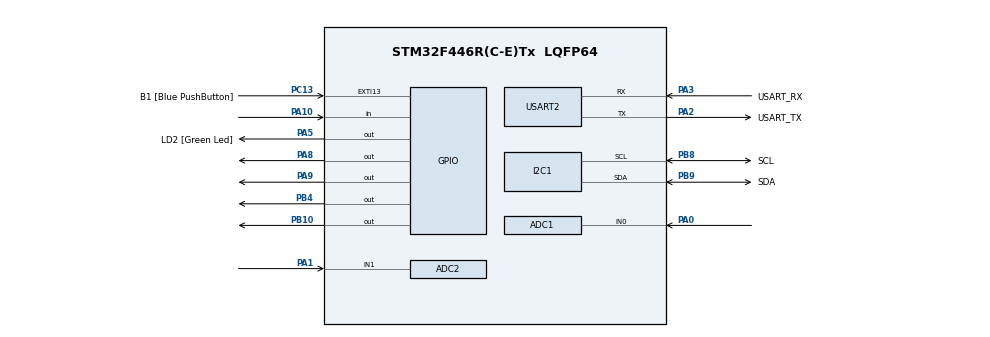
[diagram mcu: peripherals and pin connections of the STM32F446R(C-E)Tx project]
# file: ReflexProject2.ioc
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ADC1.Channel-4\#ChannelRegularConversion=ADC_CHANNEL_0
ADC1.ClockPrescaler=ADC_CLOCK_SYNC_PCLK_DIV4
ADC1.ContinuousConvMode=ENABLE
ADC1.DMAContinuousRequestsForConfigFile-ADC_Settings=LIMITED
ADC1.DataAlign=ADC_DATAALIGN_RIGHT
ADC1.InjNumberOfConversion=0
ADC1.Mode=__NULL
ADC1.NbrOfConversionFlag=1
ADC1.Rank-4\#ChannelRegularConversion=1
ADC1.Resolution=ADC_RESOLUTION_12B
ADC1.SamplingTime-4\#ChannelRegularConversion=ADC_SAMPLETIME_3CYCLES
ADC1.master=1
ADC2.Channel-2\#ChannelRegularConversion=ADC_CHANNEL_1
ADC2.ClockPrescaler=ADC_CLOCK_SYNC_PCLK_DIV4
ADC2.ContinuousConvMode=ENABLE
ADC2.DMAContinuousRequestsForConfigFile-ADC_Settings=LIMITED
ADC2.NbrOfConversionFlag=1
ADC2.Rank-2\#ChannelRegularConversion=1
ADC2.SamplingTime-2\#ChannelRegularConversion=ADC_SAMPLETIME_3CYCLES
Dma.I2C1_RX.1.Direction=DMA_PERIPH_TO_MEMORY
Dma.I2C1_RX.1.FIFOMode=DMA_FIFOMODE_DISABLE
Dma.I2C1_RX.1.Instance=DMA1_Stream0
Dma.I2C1_RX.1.MemDataAlignment=DMA_MDATAALIGN_BYTE
Dma.I2C1_RX.1.MemInc=DMA_MINC_ENABLE
Dma.I2C1_RX.1.Mode=DMA_NORMAL
Dma.I2C1_RX.1.PeriphDataAlignment=DMA_PDATAALIGN_BYTE
Dma.I2C1_RX.1.PeriphInc=DMA_PINC_DISABLE
Dma.I2C1_RX.1.Priority=DMA_PRIORITY_LOW
Dma.I2C1_TX.0.Direction=DMA_MEMORY_TO_PERIPH
Dma.I2C1_TX.0.FIFOMode=DMA_FIFOMODE_DISABLE
Dma.I2C1_TX.0.Instance=DMA1_Stream6
Dma.I2C1_TX.0.MemDataAlignment=DMA_MDATAALIGN_BYTE
Dma.I2C1_TX.0.MemInc=DMA_MINC_ENABLE
Dma.I2C1_TX.0.Mode=DMA_NORMAL
Dma.I2C1_TX.0.PeriphDataAlignment=DMA_PDATAALIGN_BYTE
Dma.I2C1_TX.0.PeriphInc=DMA_PINC_DISABLE
Dma.I2C1_TX.0.Priority=DMA_PRIORITY_LOW
Dma.Request0=I2C1_TX
Dma.Request1=I2C1_RX
FREERTOS.BinarySemaphores01=semaphoreTest,Dynamic,NULL;semaphoreMenuTimerTemp,Dynamic,NULL
FREERTOS.Queues01=potenValue,16,uint16_t,0,Dynamic,NULL,NULL
FREERTOS.Tasks01=defaultTask,24,128,StartDefaultTask,Default,NULL,Dynamic,NULL,NULL;GereLeds,24,128,GereLeds_1,Default,NULL,Dynamic,NULL,NULL;GereLcdScreen,8,128,GereLcdScreen_1,Default,NULL,Dynamic,NULL,NULL;gereRGB_LCD,8,128,changeRGBs,Default,NULL,Dynamic,NULL,NULL;gerePoten_AD0,10,128,getValueAdc,Default,NULL,Dynamic,NULL,NULL;personnalDelays,8,128,gereDelays,Default,NULL,Dynamic,NULL,NULL;stateDiagram,25,128,gereStateDiagram,Default,NULL,Dynamic,NULL,NULL
FREERTOS.configUSE_NEWLIB_REENTRANT=1
Mcu.Family=STM32F4
Mcu.Name=STM32F446R(C-E)Tx
Mcu.Package=LQFP64
NVIC.DMA1_Stream0_IRQn=true\:5\:0\:false\:false\:true\:true\:false\:true\:true
NVIC.DMA1_Stream6_IRQn=true\:5\:0\:false\:false\:true\:true\:false\:true\:true
NVIC.I2C1_ER_IRQn=true\:5\:0\:false\:false\:true\:true\:true\:true\:true
NVIC.I2C1_EV_IRQn=true\:5\:0\:false\:false\:true\:true\:true\:true\:true
NVIC.PriorityGroup=NVIC_PRIORITYGROUP_4
NVIC.TIM2_IRQn=true\:5\:0\:false\:false\:true\:true\:true\:true\:true
NVIC.TIM6_DAC_IRQn=true\:15\:0\:false\:false\:true\:false\:false\:true\:true
NVIC.TimeBase=TIM6_DAC_IRQn
NVIC.TimeBaseIP=TIM6
PA0-WKUP.Signal=ADCx_IN0
PA1.Signal=ADCx_IN1
PA10.Signal=GPIO_Input
PA13.GPIO_Label=TMS
PA13.Mode=Trace_Asynchronous_SW
PA13.Signal=SYS_JTMS-SWDIO
PA14.GPIO_Label=TCK
PA14.Mode=Trace_Asynchronous_SW
PA14.Signal=SYS_JTCK-SWCLK
PA2.GPIO_Label=USART_TX
PA2.Mode=Asynchronous
PA2.Signal=USART2_TX
PA3.GPIO_Label=USART_RX
PA3.Mode=Asynchronous
PA3.Signal=USART2_RX
PA5.GPIO_Label=LD2 [Green Led]
PA5.Signal=GPIO_Output
PA8.Signal=GPIO_Output
PA9.Signal=GPIO_Output
PB10.Signal=GPIO_Output
PB3.GPIO_Label=SWO
PB3.Mode=Trace_Asynchronous_SW
PB3.Signal=SYS_JTDO-SWO
PB4.Signal=GPIO_Output
PB8.GPIO_Label=SCL
PB8.GPIO_Pu=GPIO_PULLUP
PB8.Mode=I2C
PB8.Signal=I2C1_SCL
PB9.GPIO_Label=SDA
PB9.GPIO_Pu=GPIO_PULLUP
PB9.Mode=I2C
PB9.Signal=I2C1_SDA
PC13.GPIO_Label=B1 [Blue PushButton]
PC13.GPIO_ModeDefaultEXTI=GPIO_MODE_IT_FALLING
PC13.Signal=GPXTI13
PC14-OSC32_IN.Signal=RCC_OSC32_IN
PC15-OSC32_OUT.Signal=RCC_OSC32_OUT
PH0-OSC_IN.Mode=HSE-External-Oscillator
PH0-OSC_IN.Signal=RCC_OSC_IN
PH1-OSC_OUT.Mode=HSE-External-Oscillator
PH1-OSC_OUT.Signal=RCC_OSC_OUT
ProjectManager.HeapSize=0x200
ProjectManager.StackSize=0x400
ProjectManager.TargetToolchain=STM32CubeIDE
RCC.48MHZClocksFreq_Value=84000000
RCC.AHBCLKDivider=RCC_SYSCLK_DIV2
RCC.AHBFreq_Value=4000000
RCC.APB1CLKDivider=RCC_HCLK_DIV2
RCC.APB1Freq_Value=2000000
RCC.APB1TimFreq_Value=4000000
RCC.APB2Freq_Value=4000000
RCC.APB2TimFreq_Value=4000000
RCC.CortexFreq_Value=4000000
RCC.FLatency-AdvancedSettings=FLASH_LATENCY_0
RCC.HCLKFreq_Value=4000000
RCC.HSE_VALUE=8000000
RCC.HSI_VALUE=16000000
RCC.PLLN=336
RCC.PLLP=RCC_PLLP_DIV4
RCC.SYSCLKFreq_VALUE=8000000
RCC.SYSCLKSource=RCC_SYSCLKSOURCE_HSE
RCC.USBFreq_Value=168000000
RCC.VCOOutputFreq_Value=336000000
SH.ADCx_IN0.0=ADC1_IN0,IN0
SH.ADCx_IN1.0=ADC2_IN1,IN1
TIM2.Period=4000
TIM2.Prescaler=100
USART2.VirtualMode=VM_ASYNC
VP_FREERTOS_VS_CMSIS_V2.Mode=CMSIS_V2
VP_SYS_VS_tim6.Mode=TIM6
VP_TIM2_VS_ClockSourceINT.Mode=Internal
board=NUCLEO-F446RE

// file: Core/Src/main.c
/* USER CODE BEGIN Header */
/**
 ******************************************************************************
 * @file           : main.c
 * @brief          : Main program body
 ******************************************************************************
 * @attention
 *
 * Copyright (c) 2023 STMicroelectronics.
 * All rights reserved.
 *
 * This software is licensed under terms that can be found in the LICENSE file
 * in the root directory of this software component.
 * If no LICENSE file comes with this software, it is provided AS-IS.
 *
 ******************************************************************************
 */
/* USER CODE END Header */
#include "main.h"

#include "cmsis_os.h"

/* USER CODE BEGIN Includes */

#include "rgb_lcd.h"

#include "stdio.h"

#include "string.h"

#include "stdlib.h"

#include <time.h>
 //#include "cmsis_os2.h"

/* USER CODE END Includes */

/* USER CODE BEGIN PD */

#define NBR_COL 18

/* USER CODE END PD */

ADC_HandleTypeDef hadc1;
ADC_HandleTypeDef hadc2;

I2C_HandleTypeDef hi2c1;
DMA_HandleTypeDef hdma_i2c1_tx;
DMA_HandleTypeDef hdma_i2c1_rx;

TIM_HandleTypeDef htim2;

UART_HandleTypeDef huart2;

/* Definitions for defaultTask */
osThreadId_t defaultTaskHandle;
const osThreadAttr_t defaultTask_attributes = {
    .name = "defaultTask",
    .stack_size = 128 * 4,
    .priority = (osPriority_t) osPriorityNormal,
};
/* Definitions for GereLeds */
osThreadId_t GereLedsHandle;
const osThreadAttr_t GereLeds_attributes = {
    .name = "GereLeds",
    .stack_size = 128 * 4,
    .priority = (osPriority_t) osPriorityNormal,
};
/* Definitions for GereLcdScreen */
osThreadId_t LedsControlHandle;
const osThreadAttr_t LedsControl_attributes = {
    .name = "LedsControl",
    .stack_size = 128 * 4,
    .priority = (osPriority_t) osPriorityNormal,
};
/* Definitions for gereRGB_LCD */
osThreadId_t gereRGB_LCDHandle;
const osThreadAttr_t gereRGB_LCD_attributes = {
    .name = "gereRGB_LCD",
    .stack_size = 128 * 4,
    .priority = (osPriority_t) osPriorityNormal,
};
/* Definitions for gerePoten_AD0 */
osThreadId_t gerePoten_AD0Handle;
const osThreadAttr_t gerePoten_AD0_attributes = {
    .name = "gerePoten_AD0",
    .stack_size = 128 * 4,
    .priority = (osPriority_t) osPriorityNormal,
};
/* Definitions for personnalDelays */
osThreadId_t personnalDelaysHandle;
const osThreadAttr_t personnalDelays_attributes = {
    .name = "personnalDelays",
    .stack_size = 128 * 4,
    .priority = (osPriority_t) osPriorityNormal,
};
/* Definitions for stateDiagram */
osThreadId_t stateDiagramHandle;
const osThreadAttr_t stateDiagram_attributes = {
    .name = "stateDiagram",
    .stack_size = 128 * 4,
    .priority = (osPriority_t) osPriorityNormal,
};
/* Definitions for potenValue */
osMessageQueueId_t potenValueHandle;
const osMessageQueueAttr_t potenValue_attributes = {
    .name = "potenValue"
};
/* Definitions for semaphoreTest */
osSemaphoreId_t semaphoreTestHandle;
const osSemaphoreAttr_t semaphoreTest_attributes = {
    .name = "semaphoreTest"
};
/* Definitions for semaphoreMenuTimerTemp */
osSemaphoreId_t semaphoreMenuTimerTempHandle;
const osSemaphoreAttr_t semaphoreMenuTimerTemp_attributes = {
    .name = "semaphoreMenuTimerTemp"
};

/* USER CODE BEGIN PV */

/* Definitions for personnalDelays */
osThreadId_t gereMicHandle;
const osThreadAttr_t gereMic_attributes = {
    .name = "gereMic",
    .stack_size = 128 * 4,
    .priority = (osPriority_t) osPriorityNormal,
};

/* Definitions for potenValue */
osMessageQueueId_t micValueHandle;
const osMessageQueueAttr_t micValue_attributes = {
    .name = "micValue"
};

/* Definitions for semaphoreTest */
osSemaphoreId_t semaphoreValidMicroHandle;
const osSemaphoreAttr_t semaphoreValidMicro_attributes = {
    .name = "semaphoreValidMicro"
};

/* Definitions for stateDiagram */
osThreadId_t gereScoresHandle;
const osThreadAttr_t gereScores_attributes = {
    .name = "gereScores",
    .stack_size = 128 * 4,
    .priority = (osPriority_t) osPriorityNormal,
};

/* Definitions for semaphoreTest */
osSemaphoreId_t semaphoreDisplayScoresHandle;
const osSemaphoreAttr_t semaphoreDisplayScores_attributes = {
    .name = "semaphoreDisplayScores"
};

/* Definitions for semaphoreTest */
osSemaphoreId_t semaphoreEtatHautHandle;
const osSemaphoreAttr_t semaphoreEtatHaut_attributes = {
    .name = "semaphoreEtatHaut"
};

enum Etats {
    STARTING,
    MENU,
    TEST_1,
    TEST_2,
    TEST_3,
    SCORES
};

enum Etats etatCourant = STARTING;

int ignoreSemaphore = 0b11;
uint16_t potenValue = 0;
uint16_t micValue = 0;
char potenValue_string[20];
char micValue_string[20];

uint16_t soundSensorValue = 0;
char soundSensorValue_string[20];

int potenValueTemp = 0;

int idGame = 0;

uint8_t fullcharacter[] = {
    0b11111,
    0b11111,
    0b11111,
    0b11111,
    0b11111,
    0b11111,
    0b11111,
    0b11111
};

uint8_t emptycharacter[] = {
    0b00000,
    0b00000,
    0b00000,
    0b00000,
    0b00000,
    0b00000,
    0b00000,
    0b00000
};

// var for the firsts passages
int tempFirst = 0;

int bestRecord = 0;
char bestRecord_string[20];

int validMic = 0;
int bestRecord_temp = 0;
int timer_temp = 0;
int cpt_valMax = 0;
int oldValueMic = 0;

int bestRecordJeu1 = 0;
int bestRecordJeu2 = 0;
char bestRecordJeu1_string[20];
char bestRecordJeu2_string[20];

int etatLeds = 0;

size_t screenSize = sizeof("HUMAN SPEED TEST") - 1;

/* USER CODE END PV */

void SystemClock_Config(void);
static void MX_GPIO_Init(void);
static void MX_DMA_Init(void);
static void MX_USART2_UART_Init(void);
static void MX_ADC1_Init(void);
static void MX_ADC2_Init(void);
static void MX_I2C1_Init(void);
static void MX_TIM2_Init(void);
void StartDefaultTask(void * argument);
void GereLeds_1(void * argument);
void LedsControl(void * argument);
void changeRGBs(void * argument);
void getValueAdc(void * argument);
void gereDelays(void * argument);
void gereStateDiagram(void * argument);

/* USER CODE BEGIN PFP */

void startingLCD(void);
void menuLCD(void);
void getValueMic(void * argument);
void gereScores(void * argument);
void displayScores(void);

/* USER CODE END PFP */

/* USER CODE BEGIN 0 */

void displayTest1(void) {
    ignoreSemaphore = 0b11;
    LCD_clear();

    LCD_home();
    LCD_setCursor(0, 0);
    LCD_print("      JEU 1     ", screenSize);
    HAL_GPIO_WritePin(GPIOB, GPIO_PIN_10, 1);
    HAL_GPIO_WritePin(GPIOA, GPIO_PIN_8, 1);
    HAL_GPIO_WritePin(GPIOA, GPIO_PIN_9, 1);
    LCD_setCursor(0, 1);
    LCD_print("                ", screenSize);
    osDelay(1000);
    HAL_GPIO_WritePin(GPIOA, GPIO_PIN_8, 0);
    HAL_GPIO_WritePin(GPIOA, GPIO_PIN_9, 0);
    LCD_setCursor(0, 0);
    LCD_print("        3       ", screenSize);
    osDelay(1000);
    LCD_setCursor(0, 0);
    LCD_print("        2       ", screenSize);
    HAL_GPIO_WritePin(GPIOA, GPIO_PIN_9, 1);
    osDelay(1000);
    LCD_setCursor(0, 0);
    LCD_print("        1       ", screenSize);
    HAL_GPIO_WritePin(GPIOA, GPIO_PIN_8, 1);
    osDelay(1000);
    HAL_GPIO_WritePin(GPIOB, GPIO_PIN_10, 0);
    HAL_GPIO_WritePin(GPIOA, GPIO_PIN_8, 0);
    HAL_GPIO_WritePin(GPIOA, GPIO_PIN_9, 0);
    etatLeds = 1;
    LCD_setCursor(0, 0);
    LCD_print("      WAIT      ", screenSize);
    osDelay(1000);

    int cpt;
    int r = rand(); // Returns a pseudo-random integer between 0 and RAND_MAX.
    r = r % 5000000;

    char aye_string[16];
    int aye_res;
    bestRecord = 0;
    TIM2 -> CNT = 0;
    while (r >= cpt) {
        cpt = (bestRecord * 1000000) + ((TIM2 -> CNT) / 4);
    }
    etatLeds = 0;
    HAL_GPIO_WritePin(GPIOA, GPIO_PIN_8, 1);
    LCD_setCursor(0, 0);
    LCD_print("     PUSH       ", screenSize);
    bestRecord = 0;
    TIM2 -> CNT = 0;
    cpt = 0;
    ignoreSemaphore = 0b01;
    int iVerif = osSemaphoreAcquire(semaphoreEtatHautHandle, 5000);
    ignoreSemaphore = 0b11;
    if (iVerif == osOK) {

        cpt = (bestRecord * 1000000) + ((TIM2 -> CNT) / 4);
        aye_res = cpt;
        HAL_GPIO_WritePin(GPIOA, GPIO_PIN_8, 0);

        sprintf(aye_string, "%d", aye_res);
        LCD_setCursor(0, 1);
        LCD_print(aye_string, screenSize);
        osDelay(5000);
        if (cpt < bestRecordJeu1) {
            bestRecordJeu1 = cpt;
            strcpy(bestRecordJeu1_string, aye_string);
        }

    } else if (iVerif == osErrorTimeout) {
        LCD_setCursor(0, 1);
        LCD_print("   TROP LENT   ", screenSize);
        osDelay(5000);
    }
    LCD_setCursor(0, 0);
    LCD_print("  PRESS - PLAY  ", screenSize);
    LCD_setCursor(0, 1);
    LCD_print("   WAIT - MENU  ", screenSize);
    ignoreSemaphore = 0b10;
    iVerif = osSemaphoreAcquire(semaphoreTestHandle, 5000);
    ignoreSemaphore = 0b11;
    if (iVerif == osErrorTimeout) {
        etatCourant = MENU;
    }
}

void displayTest2(void) {
    ignoreSemaphore = 0b11;
    LCD_clear();

    LCD_home();
    LCD_setCursor(0, 0);
    LCD_print("      JEU 2     ", screenSize);
    LCD_setCursor(0, 1);
    LCD_print("                ", screenSize);
    osDelay(1000);
    LCD_setCursor(0, 0);
    LCD_print("        3       ", screenSize);
    osDelay(1000);
    LCD_setCursor(0, 0);
    LCD_print("        2       ", screenSize);
    osDelay(1000);
    LCD_setCursor(0, 0);
    LCD_print("        1       ", screenSize);
    osDelay(1000);
    LCD_setCursor(0, 0);
    LCD_print("      WAIT      ", screenSize);
    osDelay(1000);

    int cpt;
    int r = rand(); // Returns a pseudo-random integer between 0 and RAND_MAX.
    r = r % 5000000;

    char aye_string[16];
    int aye_res;
    bestRecord = 0;
    TIM2 -> CNT = 0;
    while (r >= cpt) {
        cpt = (bestRecord * 1000000) + ((TIM2 -> CNT) / 4);
    }
    osSemaphoreAcquire(semaphoreValidMicroHandle, 1);
    LCD_setCursor(0, 0);
    LCD_print("     PUSH       ", screenSize);
    bestRecord = 0;
    TIM2 -> CNT = 0;
    cpt = 0;
    micValue = 0;
    validMic = 0;
    cpt_valMax = 0;
    osSemaphoreAcquire(semaphoreValidMicroHandle, 5000);
    int iVerif = 0;
    if (iVerif == osOK) {

        cpt = (bestRecord_temp * 1000000) + (timer_temp / 4);
        aye_res = cpt;

        sprintf(aye_string, "%d", aye_res);
        LCD_setCursor(0, 1);
        LCD_print(aye_string, sizeof(aye_string) - 1);
        osDelay(5000);
        if (cpt < bestRecordJeu2) {
            bestRecordJeu2 = cpt;
            strcpy(bestRecordJeu2_string, aye_string);
        }

    } else if (iVerif == osErrorTimeout) {
        LCD_setCursor(0, 1);
        LCD_print("   TROP LENT   ", screenSize);
        osDelay(5000);
    }
    LCD_setCursor(0, 0);
    LCD_print("  PRESS - PLAY  ", screenSize);
    LCD_setCursor(0, 1);
    LCD_print("   WAIT - MENU  ", screenSize);
    ignoreSemaphore = 0b10;
    iVerif = osSemaphoreAcquire(semaphoreTestHandle, 5000);
    ignoreSemaphore = 0b11;
    if (iVerif == osErrorTimeout) {
        etatCourant = MENU;
    }
}

void startingLCD(void) {

    LCD_clear();
    LCD_home();
    LCD_setCursor(0, 0);
    LCD_print("HUMAN SPEED TEST", screenSize);
    //LCD_setCursor(0, 1);
    osDelay(1000);

    LCD_createChar(0, fullcharacter);
    LCD_createChar(1, emptycharacter);

    for (int iBcl = 0; iBcl <= 19; ++iBcl) {
        LCD_setCursor(iBcl, 1);
        LCD_write(255);
        if (iBcl >= 3) {
            LCD_setCursor(iBcl - 3, 1);
            LCD_write(1);
        }
        osDelay(30);
    }

    LCD_setCursor(0, 1);
    LCD_print("    SAE 2023    ", screenSize);
    osDelay(1000);

    for (int iBcl = 0; iBcl <= 19; ++iBcl) {
        LCD_setCursor(iBcl, 1);
        LCD_write(255);
        if (iBcl >= 3) {
            LCD_setCursor(iBcl - 3, 1);
            LCD_write(1);
        }
        osDelay(30);
    }

    LCD_setCursor(0, 1);
    LCD_print("-- JOS MAR DAV--", screenSize);
    osDelay(1000);

    for (int iBcl = 0; iBcl <= 24; ++iBcl) {

        if (iBcl >= 8) {
            LCD_setCursor(iBcl - 8, 0);
            LCD_write(1);
            LCD_setCursor(iBcl - 8, 1);
            LCD_write(1);

        }

        if (iBcl <= 16) {
            LCD_setCursor(iBcl, 0);
            LCD_write(255);
            LCD_setCursor(iBcl, 1);
            LCD_write(255);
        }

        osDelay(30);
    }
    LCD_setCursor(0, 0);
    LCD_print("     Press      ", screenSize);
    LCD_setCursor(0, 1);
    LCD_print("  to continue   ", screenSize);
}

void menuLCD(void) {

    /*if (tempFirst == 0){
        LCD_createChar(0,fullcharacter);
        LCD_setCursor(1,0);
        LCD_print("     MENU     ", 15);

        LCD_setCursor(0,0);
        LCD_write(0);
        LCD_setCursor(1,0);
        LCD_write(0);
        LCD_setCursor(0,16);
        LCD_write(0);
        LCD_setCursor(1,16);
        LCD_write(0);
        tempFirst++;
    }*/

    osMessageQueueGet(potenValueHandle, & potenValue, 0, 10);

    if (abs((potenValue - potenValueTemp)) > 10) {
        potenValueTemp = potenValue;
        if (potenValue < 1024) {
            LCD_setCursor(0, 0);
            LCD_print("     JEU 1      ", screenSize);
            LCD_setCursor(0, 1);
            LCD_print("   X  0  0  0   ", screenSize);
            idGame = 1;
        } else if (potenValue < 2048) {
            LCD_setCursor(0, 1);
            LCD_print("   0  X  0  0   ", screenSize);
            LCD_setCursor(0, 0);
            LCD_print("     JEU 2      ", screenSize);
            idGame = 2;
        } else if (potenValue < 3072) {
            LCD_setCursor(0, 1);
            LCD_print("   0  0  X  0   ", screenSize);
            LCD_setCursor(0, 0);
            LCD_print("     JEU 3      ", screenSize);
            idGame = 3;
        } else {
            LCD_setCursor(0, 1);
            LCD_print("   0  0  0  X   ", screenSize);
            LCD_setCursor(0, 0);
            LCD_print("     SCORES     ", screenSize);
            idGame = 4;
        }
        osDelay(1);
    }

}

void displayScores(void) {

    osMessageQueueGet(potenValueHandle, & potenValue, 0, osWaitForever);
    if (osThreadGetState(gereScoresHandle) == osThreadBlocked) {
        osThreadResume(gereScoresHandle);
    }
    int iVerif = osSemaphoreAcquire(semaphoreTestHandle, 1);
    if(iVerif == osErrorTimeout){
        if (abs((potenValue - potenValueTemp)) > 10) {
                potenValueTemp = potenValue;
                if (potenValue < 1024) {
                        LCD_setCursor(0, 1);
                        LCD_print(bestRecordJeu1_string, sizeof(bestRecordJeu1_string)-1);

                    idGame = 1;
                } else if (potenValue < 2048) {
                        LCD_setCursor(0, 1);
                        LCD_print(bestRecordJeu2_string, sizeof(bestRecordJeu2_string)-1);

                    idGame = 2;
                } else if (potenValue < 3072) {
                    LCD_setCursor(0, 1);
                    LCD_print("   0  0  X  0   ", screenSize);
                    idGame = 3;
                } else {
                    LCD_setCursor(0, 1);
                    LCD_print("   0  0  0  X   ", screenSize);
                    idGame = 4;
                }
            }
    }
    else{
        osThreadSuspend(gereScoresHandle);
        LCD_clear();
        etatCourant = MENU ;
    }
    osDelay(1);

}

/* USER CODE END 0 */

int main(void) {

    /* MCU Configuration--------------------------------------------------------*/

    /* Reset of all peripherals, Initializes the Flash interface and the Systick. */
    HAL_Init();

    /* Configure the system clock */
    SystemClock_Config();

    /* Initialize all configured peripherals */
    MX_GPIO_Init();
    MX_DMA_Init();
    MX_USART2_UART_Init();
    MX_ADC1_Init();
    MX_ADC2_Init();
    MX_I2C1_Init();
    MX_TIM2_Init();
    /* USER CODE BEGIN 2 */
    //LCD_begin(16, 2, 1);
    //LCD_print("AB", 2);

    /* USER CODE END 2 */

    /* Init scheduler */
    osKernelInitialize();

    /* Create the semaphores(s) */
    /* creation of semaphoreTest */
    semaphoreTestHandle = osSemaphoreNew(1, 0, & semaphoreTest_attributes);

    /* creation of semaphoreMenuTimerTemp */
    semaphoreMenuTimerTempHandle = osSemaphoreNew(1, 0, & semaphoreMenuTimerTemp_attributes);

    /* USER CODE BEGIN RTOS_SEMAPHORES */

    semaphoreValidMicroHandle = osSemaphoreNew(1, 0, & semaphoreValidMicro_attributes);

    semaphoreDisplayScoresHandle = osSemaphoreNew(1, 0, & semaphoreDisplayScores_attributes);

    semaphoreEtatHautHandle = osSemaphoreNew(1, 0, & semaphoreEtatHaut_attributes);

    /* add semaphores, ... */
    /* USER CODE END RTOS_SEMAPHORES */

    /* USER CODE BEGIN RTOS_TIMERS */

    HAL_TIM_Base_Start_IT( & htim2);
    /* start timers, add new ones, ... */
    /* USER CODE END RTOS_TIMERS */

    /* Create the queue(s) */
    /* creation of potenValue */
    potenValueHandle = osMessageQueueNew(16, sizeof(uint16_t), & potenValue_attributes);

    /* USER CODE BEGIN RTOS_QUEUES */

    micValueHandle = osMessageQueueNew(16, sizeof(uint16_t), & micValue_attributes);
    /* add queues, ... */
    /* USER CODE END RTOS_QUEUES */

    /* Create the thread(s) */
    /* creation of defaultTask */
    defaultTaskHandle = osThreadNew(StartDefaultTask, NULL, & defaultTask_attributes);

    /* creation of GereLeds */
    GereLedsHandle = osThreadNew(GereLeds_1, NULL, & GereLeds_attributes);

    /* creation of GereLcdScreen */
    LedsControlHandle = osThreadNew(LedsControl, NULL, & LedsControl_attributes);

    /* creation of gereRGB_LCD */
    gereRGB_LCDHandle = osThreadNew(changeRGBs, NULL, & gereRGB_LCD_attributes);

    /* creation of gerePoten_AD0 */
    gerePoten_AD0Handle = osThreadNew(getValueAdc, NULL, & gerePoten_AD0_attributes);

    /* creation of personnalDelays */
    personnalDelaysHandle = osThreadNew(gereDelays, NULL, & personnalDelays_attributes);

    /* creation of stateDiagram */
    stateDiagramHandle = osThreadNew(gereStateDiagram, NULL, & stateDiagram_attributes);

    /* creation of personnalDelays */
    gereMicHandle = osThreadNew(getValueMic, NULL, & gereMic_attributes);

    /* creation of stateDiagram */
    gereScoresHandle = osThreadNew(gereScores, NULL, & gereScores_attributes);

    osThreadSuspend(gereScoresHandle);
    /* Start scheduler */
    osKernelStart();

    /* We should never get here as control is now taken by the scheduler */
    /* Infinite loop */
    while (1) {

        /* USER CODE BEGIN 3 */

        // USELESS TEMPS REEL

    }
    /* USER CODE END 3 */
}

void SystemClock_Config(void) {
    RCC_OscInitTypeDef RCC_OscInitStruct = {
        0
    };
    RCC_ClkInitTypeDef RCC_ClkInitStruct = {
        0
    };

    /** Configure the main internal regulator output voltage
     */
    __HAL_RCC_PWR_CLK_ENABLE();
    __HAL_PWR_VOLTAGESCALING_CONFIG(PWR_REGULATOR_VOLTAGE_SCALE3);

    /** Initializes the RCC Oscillators according to the specified parameters
     * in the RCC_OscInitTypeDef structure.
     */
    RCC_OscInitStruct.OscillatorType = RCC_OSCILLATORTYPE_HSI;
    RCC_OscInitStruct.HSIState = RCC_HSI_ON;
    RCC_OscInitStruct.HSICalibrationValue = RCC_HSICALIBRATION_DEFAULT;
    RCC_OscInitStruct.PLL.PLLState = RCC_PLL_ON;
    RCC_OscInitStruct.PLL.PLLSource = RCC_PLLSOURCE_HSI;
    RCC_OscInitStruct.PLL.PLLM = 16;
    RCC_OscInitStruct.PLL.PLLN = 160;
    RCC_OscInitStruct.PLL.PLLP = RCC_PLLP_DIV2;
    RCC_OscInitStruct.PLL.PLLQ = 2;
    RCC_OscInitStruct.PLL.PLLR = 2;
    if (HAL_RCC_OscConfig( & RCC_OscInitStruct) != HAL_OK) {
        Error_Handler();
    }

    /** Initializes the CPU, AHB and APB buses clocks
     */
    RCC_ClkInitStruct.ClockType = RCC_CLOCKTYPE_HCLK | RCC_CLOCKTYPE_SYSCLK |
        RCC_CLOCKTYPE_PCLK1 | RCC_CLOCKTYPE_PCLK2;
    RCC_ClkInitStruct.SYSCLKSource = RCC_SYSCLKSOURCE_PLLCLK;
    RCC_ClkInitStruct.AHBCLKDivider = RCC_SYSCLK_DIV2;
    RCC_ClkInitStruct.APB1CLKDivider = RCC_HCLK_DIV2;
    RCC_ClkInitStruct.APB2CLKDivider = RCC_HCLK_DIV1;

    if (HAL_RCC_ClockConfig( & RCC_ClkInitStruct, FLASH_LATENCY_2) != HAL_OK) {
        Error_Handler();
    }
}

static void MX_ADC1_Init(void) {

    ADC_ChannelConfTypeDef sConfig = {
        0
    };

    /** Configure the global features of the ADC (Clock, Resolution, Data Alignment and number of conversion)
     */
    hadc1.Instance = ADC1;
    hadc1.Init.ClockPrescaler = ADC_CLOCK_SYNC_PCLK_DIV4;
    hadc1.Init.Resolution = ADC_RESOLUTION_12B;
    hadc1.Init.ScanConvMode = DISABLE;
    hadc1.Init.ContinuousConvMode = ENABLE;
    hadc1.Init.DiscontinuousConvMode = DISABLE;
    hadc1.Init.ExternalTrigConvEdge = ADC_EXTERNALTRIGCONVEDGE_NONE;
    hadc1.Init.ExternalTrigConv = ADC_SOFTWARE_START;
    hadc1.Init.DataAlign = ADC_DATAALIGN_RIGHT;
    hadc1.Init.NbrOfConversion = 1;
    hadc1.Init.DMAContinuousRequests = DISABLE;
    hadc1.Init.EOCSelection = ADC_EOC_SINGLE_CONV;
    if (HAL_ADC_Init( & hadc1) != HAL_OK) {
        Error_Handler();
    }

    /** Configure for the selected ADC regular channel its corresponding rank in the sequencer and its sample time.
     */
    sConfig.Channel = ADC_CHANNEL_0;
    sConfig.Rank = 1;
    sConfig.SamplingTime = ADC_SAMPLETIME_3CYCLES;
    if (HAL_ADC_ConfigChannel( & hadc1, & sConfig) != HAL_OK) {
        Error_Handler();
    }

}

static void MX_ADC2_Init(void) {

    ADC_ChannelConfTypeDef sConfig = {
        0
    };

    /** Configure the global features of the ADC (Clock, Resolution, Data Alignment and number of conversion)
     */
    hadc2.Instance = ADC2;
    hadc2.Init.ClockPrescaler = ADC_CLOCK_SYNC_PCLK_DIV4;
    hadc2.Init.Resolution = ADC_RESOLUTION_12B;
    hadc2.Init.ScanConvMode = DISABLE;
    hadc2.Init.ContinuousConvMode = ENABLE;
    hadc2.Init.DiscontinuousConvMode = DISABLE;
    hadc2.Init.ExternalTrigConvEdge = ADC_EXTERNALTRIGCONVEDGE_NONE;
    hadc2.Init.ExternalTrigConv = ADC_SOFTWARE_START;
    hadc2.Init.DataAlign = ADC_DATAALIGN_RIGHT;
    hadc2.Init.NbrOfConversion = 1;
    hadc2.Init.DMAContinuousRequests = DISABLE;
    hadc2.Init.EOCSelection = ADC_EOC_SINGLE_CONV;
    if (HAL_ADC_Init( & hadc2) != HAL_OK) {
        Error_Handler();
    }

    /** Configure for the selected ADC regular channel its corresponding rank in the sequencer and its sample time.
     */
    sConfig.Channel = ADC_CHANNEL_1;
    sConfig.Rank = 1;
    sConfig.SamplingTime = ADC_SAMPLETIME_3CYCLES;
    if (HAL_ADC_ConfigChannel( & hadc2, & sConfig) != HAL_OK) {
        Error_Handler();
    }

}

static void MX_I2C1_Init(void) {

    hi2c1.Instance = I2C1;
    hi2c1.Init.ClockSpeed = 100000;
    hi2c1.Init.DutyCycle = I2C_DUTYCYCLE_2;
    hi2c1.Init.OwnAddress1 = 0;
    hi2c1.Init.AddressingMode = I2C_ADDRESSINGMODE_7BIT;
    hi2c1.Init.DualAddressMode = I2C_DUALADDRESS_DISABLE;
    hi2c1.Init.OwnAddress2 = 0;
    hi2c1.Init.GeneralCallMode = I2C_GENERALCALL_DISABLE;
    hi2c1.Init.NoStretchMode = I2C_NOSTRETCH_DISABLE;
    if (HAL_I2C_Init( & hi2c1) != HAL_OK) {
        Error_Handler();
    }

}

static void MX_TIM2_Init(void) {

    TIM_ClockConfigTypeDef sClockSourceConfig = {
        0
    };
    TIM_MasterConfigTypeDef sMasterConfig = {
        0
    };

    htim2.Instance = TIM2;
    htim2.Init.Prescaler = 100;
    htim2.Init.CounterMode = TIM_COUNTERMODE_UP;
    htim2.Init.Period = 400000;
    htim2.Init.ClockDivision = TIM_CLOCKDIVISION_DIV1;
    htim2.Init.AutoReloadPreload = TIM_AUTORELOAD_PRELOAD_DISABLE;
    if (HAL_TIM_Base_Init( & htim2) != HAL_OK) {
        Error_Handler();
    }
    sClockSourceConfig.ClockSource = TIM_CLOCKSOURCE_INTERNAL;
    if (HAL_TIM_ConfigClockSource( & htim2, & sClockSourceConfig) != HAL_OK) {
        Error_Handler();
    }
    sMasterConfig.MasterOutputTrigger = TIM_TRGO_RESET;
    sMasterConfig.MasterSlaveMode = TIM_MASTERSLAVEMODE_DISABLE;
    if (HAL_TIMEx_MasterConfigSynchronization( & htim2, & sMasterConfig) != HAL_OK) {
        Error_Handler();
    }

}

static void MX_USART2_UART_Init(void) {

    huart2.Instance = USART2;
    huart2.Init.BaudRate = 115200;
    huart2.Init.WordLength = UART_WORDLENGTH_8B;
    huart2.Init.StopBits = UART_STOPBITS_1;
    huart2.Init.Parity = UART_PARITY_NONE;
    huart2.Init.Mode = UART_MODE_TX_RX;
    huart2.Init.HwFlowCtl = UART_HWCONTROL_NONE;
    huart2.Init.OverSampling = UART_OVERSAMPLING_16;
    if (HAL_UART_Init( & huart2) != HAL_OK) {
        Error_Handler();
    }

}

static void MX_DMA_Init(void) {

    /* DMA controller clock enable */
    __HAL_RCC_DMA1_CLK_ENABLE();

    /* DMA interrupt init */
    /* DMA1_Stream0_IRQn interrupt configuration */
    HAL_NVIC_SetPriority(DMA1_Stream0_IRQn, 5, 0);
    HAL_NVIC_EnableIRQ(DMA1_Stream0_IRQn);
    /* DMA1_Stream6_IRQn interrupt configuration */
    HAL_NVIC_SetPriority(DMA1_Stream6_IRQn, 5, 0);
    HAL_NVIC_EnableIRQ(DMA1_Stream6_IRQn);

}

static void MX_GPIO_Init(void) {
    GPIO_InitTypeDef GPIO_InitStruct = {
        0
    };

    /* GPIO Ports Clock Enable */
    __HAL_RCC_GPIOC_CLK_ENABLE();
    __HAL_RCC_GPIOH_CLK_ENABLE();
    __HAL_RCC_GPIOA_CLK_ENABLE();
    __HAL_RCC_GPIOB_CLK_ENABLE();

    /*Configure GPIO pin Output Level */
    HAL_GPIO_WritePin(GPIOA, LD2_Pin | GPIO_PIN_8 | GPIO_PIN_9, GPIO_PIN_RESET);

    /*Configure GPIO pin Output Level */
    HAL_GPIO_WritePin(GPIOB, GPIO_PIN_10 | GPIO_PIN_4, GPIO_PIN_RESET);

    /*Configure GPIO pin : B1_Pin */
    GPIO_InitStruct.Pin = B1_Pin;
    GPIO_InitStruct.Mode = GPIO_MODE_IT_FALLING;
    GPIO_InitStruct.Pull = GPIO_NOPULL;
    HAL_GPIO_Init(B1_GPIO_Port, & GPIO_InitStruct);

    /*Configure GPIO pins : LD2_Pin PA8 PA9 */
    GPIO_InitStruct.Pin = LD2_Pin | GPIO_PIN_8 | GPIO_PIN_9;
    GPIO_InitStruct.Mode = GPIO_MODE_OUTPUT_PP;
    GPIO_InitStruct.Pull = GPIO_NOPULL;
    GPIO_InitStruct.Speed = GPIO_SPEED_FREQ_LOW;
    HAL_GPIO_Init(GPIOA, & GPIO_InitStruct);

    /*Configure GPIO pins : PB10 PB4 */
    GPIO_InitStruct.Pin = GPIO_PIN_10 | GPIO_PIN_4;
    GPIO_InitStruct.Mode = GPIO_MODE_OUTPUT_PP;
    GPIO_InitStruct.Pull = GPIO_NOPULL;
    GPIO_InitStruct.Speed = GPIO_SPEED_FREQ_LOW;
    HAL_GPIO_Init(GPIOB, & GPIO_InitStruct);

    /*Configure GPIO pin : PA10 */
    GPIO_InitStruct.Pin = GPIO_PIN_10;
    GPIO_InitStruct.Mode = GPIO_MODE_INPUT;
    GPIO_InitStruct.Pull = GPIO_NOPULL;
    HAL_GPIO_Init(GPIOA, & GPIO_InitStruct);

}

void StartDefaultTask(void * argument) {
    for (;;) {
        osDelay(1);
    }
}

void GereLeds_1(void * argument) {
    /* USER CODE BEGIN GereLeds_1 */
    int buttonRelease = 1;
    int buttonReleaseEtatHaut = 1;
    /* Infinite loop */
    for (;;) {

        if (HAL_GPIO_ReadPin(GPIOA, GPIO_PIN_10) == 1) {
            buttonRelease = 1;
            if (buttonReleaseEtatHaut == 1) {
                buttonReleaseEtatHaut = 0;
                if ((ignoreSemaphore & 0b10) == 0) {
                    osSemaphoreRelease(semaphoreEtatHautHandle);
                }
            }
        } else {
            buttonReleaseEtatHaut = 1;
            if (buttonRelease == 1) {
                buttonRelease = 0;
                if ((ignoreSemaphore & 0b01) == 0) {
                    osSemaphoreRelease(semaphoreTestHandle);
                }
            }
        }

        osDelay(1);

    }
    /* USER CODE END GereLeds_1 */
}

void LedsControl(void * argument) {
    /* USER CODE BEGIN GereLcdScreen_1 */

    //Etats = STARTING;

    int temp_leds = 0;
    /* Infinite loop */
    for (;;) {
        if (etatLeds == 1) {
            if (temp_leds == 0) {
                temp_leds = 1;
                HAL_GPIO_WritePin(GPIOB, GPIO_PIN_10, 1);
            } else {
                temp_leds = 0;
                HAL_GPIO_WritePin(GPIOB, GPIO_PIN_10, 0);
            }

            osDelay(90);
        }
        osDelay(10);
    }
    /* USER CODE END GereLcdScreen_1 */
}

void gereScores(void * argument) {
    /* USER CODE BEGIN GereLcdScreen_1 */

    /* Infinite loop */
    for (;;) {

//        LCD_setCursor(0, 0);
//        LCD_print("azeazeaze", sizeof("azeazeaze")-1);
//        osDelay(1);
        osMessageQueueGet(potenValueHandle, & potenValue, 0, osWaitForever);
        switch (idGame) {
            case 1:
                LCD_setCursor(0, 0);
                LCD_print("     JEU 1      ", screenSize);
                osDelay(1000);
                LCD_setCursor(0, 0);
                LCD_print("   X  0  0  0   ", screenSize);
                osDelay(1000);
                break;
            case 2:
                LCD_setCursor(0, 0);
                LCD_print("     JEU 2      ", screenSize);
                osDelay(1000);
                LCD_setCursor(0, 0);
                LCD_print("   0  X  0  0   ", screenSize);
                osDelay(1000);
                break;
            case 3:
                LCD_setCursor(0, 0);
                LCD_print("     JEU 3      ", screenSize);
                osDelay(1000);
                LCD_setCursor(0, 0);
                LCD_print("   0  0  X  0   ", screenSize);
                osDelay(1000);
                break;
            case 4:
                LCD_setCursor(0, 0);
                LCD_print("       -        ", screenSize);
                osDelay(1000);
                LCD_setCursor(0, 0);
                LCD_print("   0  0  0  X   ", screenSize);
                osDelay(1000);
                break;
            default:
                break;
            }
            osDelay(1);
        }
}

void changeRGBs(void * argument) {
    /* USER CODE BEGIN changeRGBs */
    int R = 0;
    int G = 100;
    int B = 200;
    int temp1 = 0;
    int temp2 = 0;
    int temp3 = 0;
    etatCourant = STARTING;
    /* Infinite loop */
    for (;;) {
        void defilColors() {
            if (temp1 == 0) {
                if (R == 254) {
                    temp1 = 1;
                }
                R++;
            } else {
                if (R == 1) {
                    temp1 = 0;
                }
                R--;
            }

            if (temp2 == 0) {
                if (G == 254) {
                    temp2 = 1;
                }
                G++;
            } else {
                if (G == 1) {
                    temp2 = 0;
                }
                G--;
            }

            if (temp3 == 0) {
                if (B == 254) {
                    temp3 = 1;
                }
                B++;
            } else {
                if (B == 1) {
                    temp3 = 0;
                }
                B--;
            }

            LCD_setRGB(R, G, B);
            osDelay(10);
        }
        if ((etatCourant == STARTING) || (etatCourant == MENU)) {
            defilColors();
        }
        /*
              else if{
              }
              else if
              }*/
        osDelay(1);

    }
    /* USER CODE END changeRGBs */
}

void getValueAdc(void * argument) {
    /* USER CODE BEGIN getValueAdc */
    /* Infinite loop */
    for (;;) {
        HAL_ADC_Start( & hadc1);
        HAL_ADC_PollForConversion( & hadc1, 20);
        potenValue = HAL_ADC_GetValue( & hadc1);
        sprintf(potenValue_string, "%d", potenValue);
        osMessageQueuePut(potenValueHandle, & potenValue, 0, 0);
        osDelay(1);
        //HAL_ADC_stop

    }
    /* USER CODE END getValueAdc */
}

void getValueMic(void * argument) {
    /* USER CODE BEGIN getValueAdc */
    micValue = 0;
    validMic = 0;
    cpt_valMax = 0;
    /* Infinite loop */
    for (;;) {
        HAL_ADC_Start( & hadc2);
        HAL_ADC_PollForConversion( & hadc2, 20);
        micValue = HAL_ADC_GetValue( & hadc2);
        sprintf(micValue_string, "%d", micValue);
        /*LCD_setCursor(0, 0);
        LCD_print(micValue_string, sizeof(micValue_string)-1);*/

        if (micValue > 1500) {
            if (cpt_valMax == 0) {
                bestRecord_temp = bestRecord;
                timer_temp = TIM2 -> CNT;
            }

            cpt_valMax++;
            if (cpt_valMax == 4) {
                osSemaphoreRelease(semaphoreValidMicroHandle);
                cpt_valMax = 0;
            }
        } else {
            cpt_valMax = 0;
        }
        osDelay(1);
        //HAL_ADC_stop

    }
    /* USER CODE END getValueAdc */
}

void gereDelays(void * argument) {
    /* USER CODE BEGIN gereDelays */
    /* Infinite loop */
    for (;;) {
        /*if(abs((potenValue - potenValueTemp)) > 20){
            HAL_GPIO_WritePin(GPIOB, GPIO_PIN_10, 1);
            HAL_GPIO_WritePin(GPIOA, GPIO_PIN_8, 1);
            HAL_GPIO_WritePin(GPIOA, GPIO_PIN_9, 1);
            osSemaphoreRelease(semaphoreMenuTimerTempHandle);
        }*/
        osDelay(500);
    }
    /* USER CODE END gereDelays */
}

/* USER CODE END Header_gereStateDiagram */
void gereStateDiagram(void * argument) {
    /* USER CODE BEGIN gereStateDiagram */
    /* Infinite loop */
    LCD_begin(16, 2, 0);
    srand(time(NULL)); // Initialization, should only be called once.
    HAL_GPIO_WritePin(GPIOB, GPIO_PIN_10, 0);
    HAL_GPIO_WritePin(GPIOA, GPIO_PIN_8, 0);
    HAL_GPIO_WritePin(GPIOA, GPIO_PIN_9, 0);

    for (;;) {

        switch (etatCourant) {
        case STARTING:

            /*menuLCD();
            osDelay(1);*/
            ignoreSemaphore = 0b11;
            startingLCD();
            ignoreSemaphore = 0b10;
            osSemaphoreAcquire(semaphoreTestHandle, osWaitForever);
            etatCourant = MENU;

            break;
        case MENU:
            //LCD_clear();
            menuLCD();

            if (osSemaphoreAcquire(semaphoreTestHandle, 1) == osOK) {
                switch (idGame) {
                case 1:
                    etatCourant = TEST_1;
                    break;
                case 2:
                    etatCourant = TEST_2;
                    break;
                case 3:
                    etatCourant = TEST_3;
                    break;
                case 4:
                    etatCourant = SCORES;
                    break;
                default:
                    break;
                }
            }

            break;
        case TEST_1:
            displayTest1();

            break;
        case TEST_2:
            displayTest2();
            break;
        case TEST_3:
            break;
        case SCORES:
            displayScores();
            break;
        default:
            break;
        }
        osDelay(1);
    }
    /* USER CODE END gereStateDiagram */
}

void HAL_TIM_PeriodElapsedCallback(TIM_HandleTypeDef * htim) {
    if (htim -> Instance == TIM6) {
        HAL_IncTick();
    }
    /* USER CODE BEGIN Callback 1 */
    if (htim -> Instance == htim2.Instance) {
        bestRecord++;
    }

    /* USER CODE END Callback 1 */
}

void Error_Handler(void) {
    __disable_irq();
    while (1) {}
}
